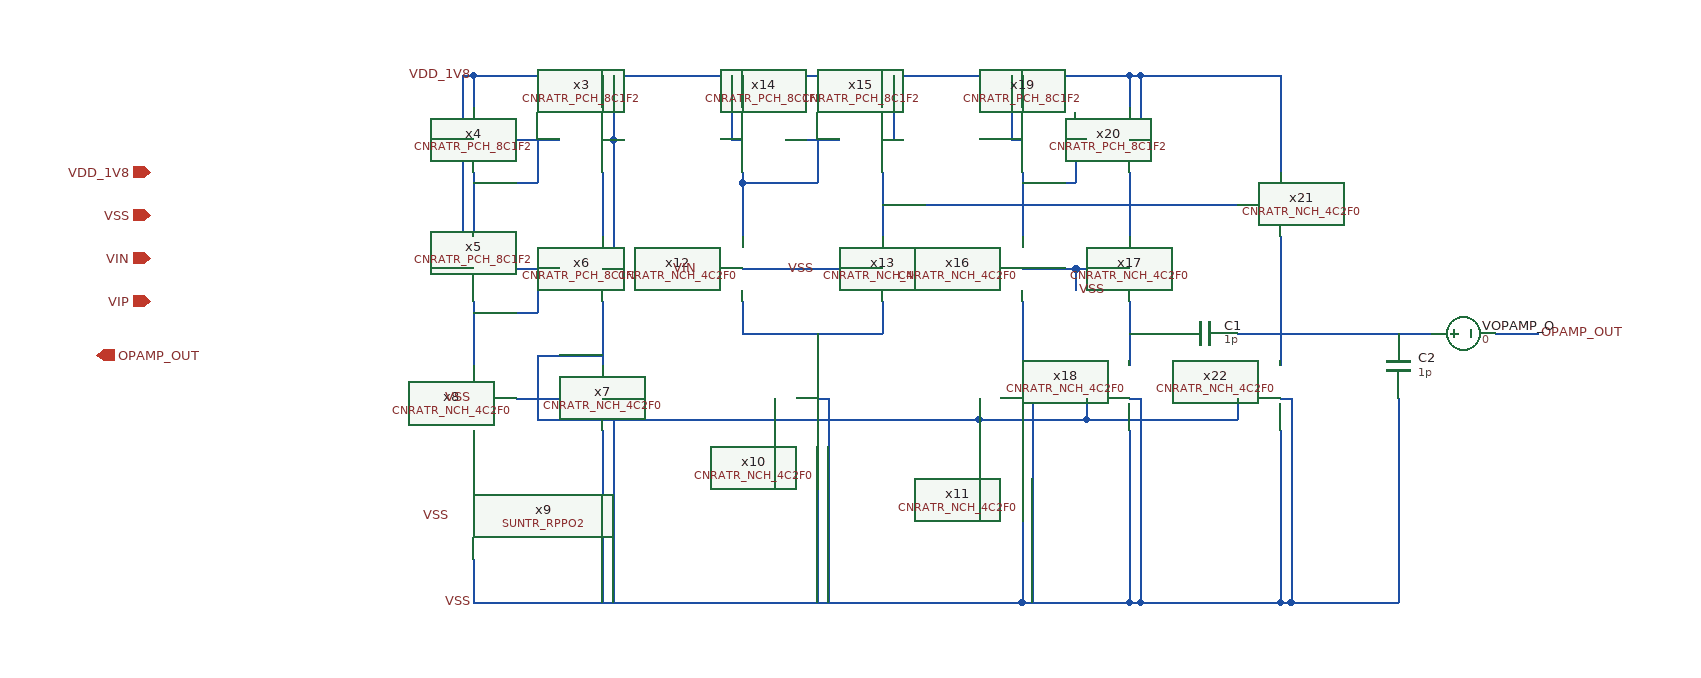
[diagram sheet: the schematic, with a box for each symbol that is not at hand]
v {xschem version=3.4.4 file_version=1.2
}
G {}
K {}
V {}
S {}
E {}
N 410 -450 410 -390 {
lab=#net1}
N 410 -330 410 -270 {
lab=#net2}
N 410 -210 410 -170 {
lab=#net3}
N 450 -240 490 -240 {
lab=#net4}
N 450 -360 490 -360 {
lab=#net2}
N 450 -480 490 -480 {
lab=#net1}
N 470 -480 470 -440 {
lab=#net1}
N 410 -440 470 -440 {
lab=#net1}
N 470 -360 470 -320 {
lab=#net2}
N 410 -320 470 -320 {
lab=#net2}
N 530 -450 530 -390 {
lab=#net5}
N 530 -330 530 -270 {
lab=#net4}
N 470 -280 470 -240 {
lab=#net4}
N 470 -280 530 -280 {
lab=#net4}
N 660 -440 660 -390 {
lab=#net6}
N 790 -440 790 -390 {
lab=#net7}
N 790 -330 790 -300 {
lab=#net8}
N 660 -300 790 -300 {
lab=#net8}
N 660 -330 660 -300 {
lab=#net8}
N 730 -300 730 -270 {
lab=#net8}
N 790 -450 790 -440 {
lab=#net7}
N 660 -450 660 -440 {
lab=#net6}
N 700 -480 750 -480 {
lab=#net6}
N 730 -480 730 -440 {
lab=#net6}
N 660 -440 730 -440 {
lab=#net6}
N 410 -540 410 -510 {
lab=VDD_1V8}
N 410 -540 790 -540 {
lab=VDD_1V8}
N 790 -540 790 -510 {
lab=VDD_1V8}
N 660 -540 660 -510 {
lab=VDD_1V8}
N 530 -540 530 -510 {
lab=VDD_1V8}
N 410 -90 410 -50 {
lab=VSS}
N 410 -50 920 -50 {
lab=VSS}
N 920 -210 920 -50 {
lab=VSS}
N 730 -210 730 -50 {
lab=VSS}
N 530 -210 530 -50 {
lab=VSS}
N 470 -240 470 -220 {
lab=#net4}
N 470 -220 880 -220 {
lab=#net4}
N 880 -240 880 -220 {
lab=#net4}
N 690 -240 690 -220 {
lab=#net4}
N 400 -480 410 -480 {
lab=VDD_1V8}
N 400 -480 400 -360 {
lab=VDD_1V8}
N 400 -360 410 -360 {
lab=VDD_1V8}
N 530 -480 540 -480 {
lab=VDD_1V8}
N 540 -480 540 -360 {
lab=VDD_1V8}
N 530 -360 540 -360 {
lab=VDD_1V8}
N 660 -360 790 -360 {
lab=VSS}
N 960 -360 980 -360 {
lab=VSS}
N 970 -360 970 -340 {
lab=VSS}
N 920 -360 970 -360 {
lab=VSS}
N 970 -360 1020 -360 {
lab=VSS}
N 880 -220 980 -220 {
lab=#net4}
N 980 -240 980 -220 {
lab=#net4}
N 1020 -210 1020 -50 {
lab=VSS}
N 920 -50 1020 -50 {
lab=VSS}
N 1020 -330 1020 -270 {
lab=#net9}
N 920 -330 920 -270 {
lab=#net10}
N 960 -480 980 -480 {
lab=#net11}
N 920 -450 920 -390 {
lab=#net11}
N 1020 -450 1020 -390 {
lab=#net7}
N 970 -480 970 -440 {
lab=#net11}
N 920 -440 970 -440 {
lab=#net11}
N 790 -540 1020 -540 {
lab=VDD_1V8}
N 1020 -540 1020 -510 {
lab=VDD_1V8}
N 920 -540 920 -510 {
lab=VDD_1V8}
N 540 -540 540 -480 {
lab=VDD_1V8}
N 400 -540 400 -480 {
lab=VDD_1V8}
N 400 -540 410 -540 {
lab=VDD_1V8}
N 650 -480 660 -480 {
lab=VDD_1V8}
N 650 -540 650 -480 {
lab=VDD_1V8}
N 790 -480 800 -480 {
lab=VDD_1V8}
N 800 -540 800 -480 {
lab=VDD_1V8}
N 910 -480 920 -480 {
lab=VDD_1V8}
N 910 -540 910 -480 {
lab=VDD_1V8}
N 1020 -480 1030 -480 {
lab=VDD_1V8}
N 1030 -540 1030 -480 {
lab=VDD_1V8}
N 1020 -540 1030 -540 {
lab=VDD_1V8}
N 530 -240 540 -240 {
lab=VSS}
N 540 -240 540 -50 {
lab=VSS}
N 730 -240 740 -240 {
lab=VSS}
N 740 -240 740 -50 {
lab=VSS}
N 920 -240 930 -240 {
lab=VSS}
N 930 -240 930 -50 {
lab=VSS}
N 1020 -240 1030 -240 {
lab=VSS}
N 1030 -240 1030 -50 {
lab=VSS}
N 1020 -50 1030 -50 {
lab=VSS}
N 1020 -420 1120 -420 {
lab=#net7}
N 790 -420 1020 -420 {
lab=#net7}
N 1160 -540 1160 -450 {
lab=VDD_1V8}
N 1030 -540 1160 -540 {
lab=VDD_1V8}
N 980 -220 1120 -220 {
lab=#net4}
N 1120 -240 1120 -220 {
lab=#net4}
N 1160 -390 1160 -270 {
lab=#net12}
N 1160 -210 1160 -50 {
lab=VSS}
N 1030 -50 1160 -50 {
lab=VSS}
N 1160 -240 1170 -240 {
lab=VSS}
N 1170 -240 1170 -50 {
lab=VSS}
N 1160 -50 1170 -50 {
lab=VSS}
N 1020 -300 1060 -300 {
lab=#net9}
N 1120 -300 1160 -300 {
lab=#net12}
N 1160 -300 1270 -300 {
lab=#net12}
N 1270 -240 1270 -50 {
lab=VSS}
N 1170 -50 1270 -50 {
lab=VSS}
N 1270 -300 1300 -300 {
lab=#net12}
N 1360 -300 1400 -300 {
lab=OPAMP_OUT}
C {devices/ipin.sym} 110 -450 0 0 {name=p1 lab=VDD_1V8}
C {devices/ipin.sym} 110 -410 0 0 {name=p2 lab=VSS}
C {devices/ipin.sym} 110 -370 0 0 {name=p3 lab=VIN}
C {devices/ipin.sym} 110 -330 0 0 {name=p4 lab=VIP}
C {devices/opin.sym} 60 -280 0 0 {name=p5 lab=OPAMP_OUT}
C {/home/local/syverhar/pro/aicex/ip/cnr_atr_sky130nm/design/CNR_ATR_SKY130NM/CNRATR_PCH_8C1F2.sym} 490 -480 0 0 {name=x3 }
C {/home/local/syverhar/pro/aicex/ip/cnr_atr_sky130nm/design/CNR_ATR_SKY130NM/CNRATR_PCH_8C1F2.sym} 450 -480 0 1 {name=x4 }
C {/home/local/syverhar/pro/aicex/ip/cnr_atr_sky130nm/design/CNR_ATR_SKY130NM/CNRATR_PCH_8C1F2.sym} 450 -360 0 1 {name=x5 }
C {/home/local/syverhar/pro/aicex/ip/cnr_atr_sky130nm/design/CNR_ATR_SKY130NM/CNRATR_PCH_8C1F2.sym} 490 -360 0 0 {name=x6 }
C {/home/local/syverhar/pro/aicex/ip/cnr_atr_sky130nm/design/CNR_ATR_SKY130NM/CNRATR_NCH_4C2F0.sym} 490 -240 0 0 {name=x7 }
C {/home/local/syverhar/pro/aicex/ip/cnr_atr_sky130nm/design/CNR_ATR_SKY130NM/CNRATR_NCH_4C2F0.sym} 450 -240 0 1 {name=x8 }
C {SUN_TR_SKY130NM/SUNTR_RPPO2.sym} 410 -170 1 0 {name=x9 }
C {/home/local/syverhar/pro/aicex/ip/cnr_atr_sky130nm/design/CNR_ATR_SKY130NM/CNRATR_NCH_4C2F0.sym} 690 -240 0 0 {name=x10 }
C {/home/local/syverhar/pro/aicex/ip/cnr_atr_sky130nm/design/CNR_ATR_SKY130NM/CNRATR_NCH_4C2F0.sym} 880 -240 0 0 {name=x11 }
C {/home/local/syverhar/pro/aicex/ip/cnr_atr_sky130nm/design/CNR_ATR_SKY130NM/CNRATR_NCH_4C2F0.sym} 620 -360 0 0 {name=x12 }
C {/home/local/syverhar/pro/aicex/ip/cnr_atr_sky130nm/design/CNR_ATR_SKY130NM/CNRATR_NCH_4C2F0.sym} 830 -360 0 1 {name=x13 }
C {/home/local/syverhar/pro/aicex/ip/cnr_atr_sky130nm/design/CNR_ATR_SKY130NM/CNRATR_PCH_8C1F2.sym} 700 -480 0 1 {name=x14 }
C {/home/local/syverhar/pro/aicex/ip/cnr_atr_sky130nm/design/CNR_ATR_SKY130NM/CNRATR_PCH_8C1F2.sym} 750 -480 0 0 {name=x15 }
C {devices/lab_pin.sym} 410 -540 0 0 {name=p6 sig_type=std_logic lab=VDD_1V8}
C {devices/lab_pin.sym} 410 -50 0 0 {name=p7 sig_type=std_logic lab=VSS}
C {devices/lab_pin.sym} 620 -360 0 0 {name=p8 sig_type=std_logic lab=VIN}
C {devices/lab_pin.sym} 830 -360 0 1 {name=p9 sig_type=std_logic lab=VIP}
C {devices/lab_pin.sym} 390 -130 0 0 {name=p10 sig_type=std_logic lab=VSS}
C {devices/lab_pin.sym} 410 -240 0 0 {name=p11 sig_type=std_logic lab=VSS}
C {devices/lab_pin.sym} 700 -360 0 1 {name=p16 sig_type=std_logic lab=VSS}
C {/home/local/syverhar/pro/aicex/ip/cnr_atr_sky130nm/design/CNR_ATR_SKY130NM/CNRATR_NCH_4C2F0.sym} 960 -360 0 1 {name=x16 }
C {/home/local/syverhar/pro/aicex/ip/cnr_atr_sky130nm/design/CNR_ATR_SKY130NM/CNRATR_NCH_4C2F0.sym} 980 -360 0 0 {name=x17 }
C {devices/lab_pin.sym} 970 -340 0 1 {name=p19 sig_type=std_logic lab=VSS}
C {/home/local/syverhar/pro/aicex/ip/cnr_atr_sky130nm/design/CNR_ATR_SKY130NM/CNRATR_NCH_4C2F0.sym} 980 -240 0 0 {name=x18 }
C {/home/local/syverhar/pro/aicex/ip/cnr_atr_sky130nm/design/CNR_ATR_SKY130NM/CNRATR_PCH_8C1F2.sym} 960 -480 0 1 {name=x19 }
C {/home/local/syverhar/pro/aicex/ip/cnr_atr_sky130nm/design/CNR_ATR_SKY130NM/CNRATR_PCH_8C1F2.sym} 980 -480 0 0 {name=x20 }
C {/home/local/syverhar/pro/aicex/ip/cnr_atr_sky130nm/design/CNR_ATR_SKY130NM/CNRATR_NCH_4C2F0.sym} 1120 -420 0 0 {name=x21 }
C {/home/local/syverhar/pro/aicex/ip/cnr_atr_sky130nm/design/CNR_ATR_SKY130NM/CNRATR_NCH_4C2F0.sym} 1120 -240 0 0 {name=x22 }
C {devices/capa.sym} 1090 -300 3 0 {name=C1
m=1
value=1p
footprint=1206
device="ceramic capacitor"}
C {devices/capa.sym} 1270 -270 0 0 {name=C2
m=1
value=1p
footprint=1206
device="ceramic capacitor"}
C {devices/lab_pin.sym} 1400 -300 0 1 {name=p12 sig_type=std_logic lab=OPAMP_OUT}
C {devices/vsource.sym} 1330 -300 3 0 {name=VOPAMP_O value=0 savecurrent=false}
